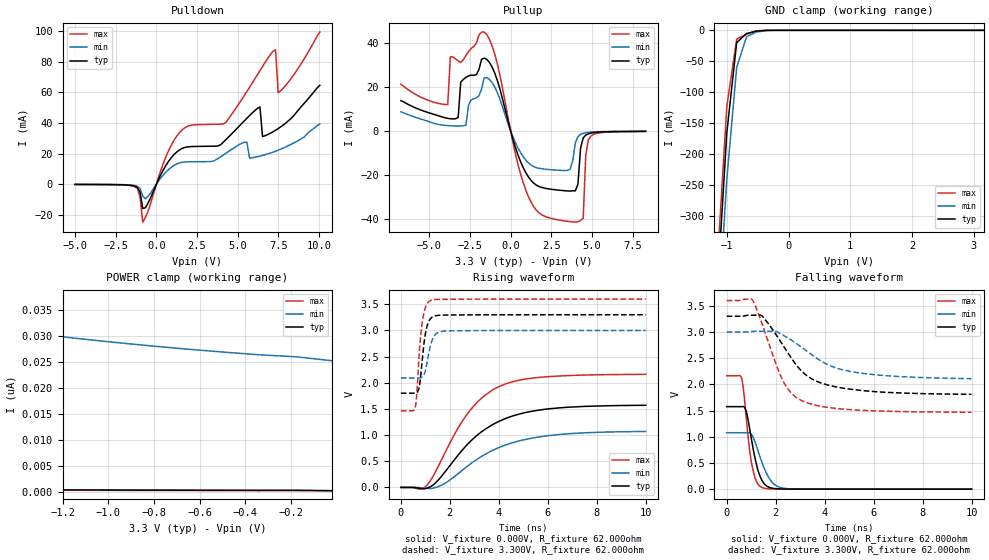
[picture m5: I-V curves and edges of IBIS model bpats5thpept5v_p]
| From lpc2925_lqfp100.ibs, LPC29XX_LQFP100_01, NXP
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| |   Rev 0.20 IBIS Model Design Automation Generation   |
| |   N O N - S I L I C O N   C O R R E L A T E D   |
| |   This IBIS [Model] is pre-Beta tactical support   |
| |  Note: this IBIS [Model] contains clamp curves generated   |
| |   through simulation which should not be relied upon   |
| Pccmos14 hliolib_nlm 4.0.1
|   0.18 um 3.3V pad library
|   six level metal
|   dual oxide
|   single threshold voltage
|   nominal line mixed supply
|   parasitic extracted netlists
| Process block c14
| bpats5thpept5v
|   Bidirectional Pad 3v3
|   3state Output
|   Plain Input
|   5ns Slew Rate control
|   CMOS
|   Programmable between
|   - (p1=0, p2=1) plain input
|   - (p1=0, p2=0) with Pull Up
|   - (p1=1, p2=1) with Pull Down
|   - (p1=1, p2=0) with Repeater
|   Characterized at Core 1.8V and I/O 3.3V
| Plain input Mode (p1=0, p2=1)
[Model]   bpats5thpept5v_p | of bpats5thpept5v
Model_type   I/O
Polarity   Non-Inverting
Enable   Active-Low
|  Reciever Thresholds
Vinl   = 0.99V
Vinh   = 2.31V
| AC Test Load Conditions
Vref   = 0
Cref   = 1.2e-11
Rref   = 1000000000
Vmeas   = 1.65
| [Process Range]   typical   min   max
| C_comp edge width   400.000ps   400.000ps   400.000ps
| C_comp Tstrobe   40.000fs   40.000fs   40.000fs
C_comp   2.539pF   2.402pF   2.679pF
[Temperature Range]   25   125   -40
[Voltage Range]   3.30V   3.00V   3.60V
[GND Clamp Reference]   0.00V   0.00V   0.00V
[Pulldown Reference]   0.00V   0.00V   0.00V
[POWER Clamp Reference]   3.30V   3.00V   3.60V
[Pullup Reference]   3.30V   3.00V   3.60V
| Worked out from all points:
|   slope of the pulldown table from 0 to 0.495 V, typ, clamps not added: 46.5 ohm
|   slope of the pullup table from 0 to 0.495 V, typ, clamps not added: 41.9 ohm
|   GND clamp passes 1 mA (typ) near -0.48 V on its own axis
|   rising waveform, V_fixture 0.000V, R_fixture 62.000ohm: 20-80 % time 2.15ns typ, 2.37ns min, 1.8ns max; typ from 0 V to 1.57 V
|   falling waveform, V_fixture 0.000V, R_fixture 62.000ohm: 20-80 % time 411ps typ, 539ps min, 319ps max; typ from 1.57 V to 0 V
|   rising waveform, V_fixture 3.300V, R_fixture 62.000ohm: 20-80 % time 225ps typ, 260ps min, 215ps max; typ from 1.8 V to 3.3 V
|   falling waveform, V_fixture 3.300V, R_fixture 62.000ohm: 20-80 % time 1.53ns typ, 1.95ns min, 1.1ns max; typ from 3.3 V to 1.81 V
[GND Clamp]
| ref voltage   0.00V   0.00V   0.00V
|   Voltage   I(typ)   I(min)   I(max)
-5V       -7.933A    -7.953A    -7.929A
-1.16V    -429.6mA   -501mA     -389.4mA
-1V       -166.1mA   -240.8mA   -123.1mA
-840mV    -19.82mA   -60.19mA   -14.18mA
-680mV    -5.225mA   -10.28mA   -6.152mA
-520mV    -1.304mA   -2.7mA     -818.1uA
-200mV    -132.3nA   -9.731uA   -2.769nA
3.16V     216.3pA    26.32nA    148.8pA
[Power Clamp]   | Vtable = Vcc - Vpad
| ref voltage   3.30V   3.00V   3.60V
|   Voltage   I(typ)   I(min)   I(max)
-6.74V    1.379nA    125.5nA    723.8pA
-4.66V    863pA      70.57nA    560.5pA
-2.42V    509.5pA    38.28nA    388.3pA
-2.26V    489.9pA    36.89nA    376pA
-2.1V     470.8pA    35.59nA    363.8pA
-1.78V    434.1pA    33.27nA    339.4pA
-1.62V    416.5pA    32.24nA    327.2pA
-1.3V     382.5pA    30.41nA    302.8pA
-820mV    334.3pA    28.18nA    266.3pA
-340mV    288.9pA    26.43nA    229.9pA
-180mV    281.7pA    26.06nA    265.9pA
-20mV     233pA      25.29nA    176.8pA
[Pulldown]
| ref voltage   0.00V   0.00V   0.00V
|   Voltage   I(typ)   I(min)   I(max)
-5V       -187.5uA   -145.8uA   -211.8uA
-1.32V    -1.32mA    -939.5uA   -1.723mA
-1V       -5.324mA   -2.961mA   -8.618mA
-840mV    -15.95mA   -7.735mA   -24.89mA
1.4V      22.26mA    13.79mA    33.48mA
4.28V     29.27mA    20.27mA    40.55mA
5.56V     43.15mA    27.33mA    60.63mA
6.36V     50.49mA    18.36mA    74.24mA
6.52V     31.16mA    18.79mA    76.97mA
7.32V     35.27mA    21.55mA    87.95mA
7.48V     36.36mA    22.22mA    59.78mA
10.04V    64.68mA    39.32mA    99.49mA
[Pullup]   | Vtable = Vcc - Vpad
| ref voltage   3.30V   3.00V   3.60V
|   Voltage   I(typ)   I(min)   I(max)
-6.74V    13.67mA    8.53mA     21.02mA
-3.86V    5.598mA    2.307mA    11.88mA
-3.7V     5.416mA    2.227mA    33.56mA
-2.74V    24.29mA    2.441mA    34.22mA
-1.62V    32.99mA    24.07mA    44.83mA
940mV     -19.18mA   -13.46mA   -27.14mA
2.86V     -27.01mA   -17.98mA   -40.52mA
3.98V     -27.37mA   -5.511mA   -41.66mA
4.46V     -3.36mA    -1.235mA   -39.89mA
4.62V     -2.02mA    -961.6uA   -11.27mA
4.94V     -1.105mA   -662.3uA   -2.417mA
8.3V      -310.5uA   -276.1uA   -365.1uA
[Ramp]
R_load   = 62.000ohm
|   dV/dt(typ)   dV/dt(min)   dV/dt(max)
dV/dt_r   720.631mV/2.205ns   482.682mV/2.365ns   1.049V/2.035ns
dV/dt_f   674.653mV/1.565ns   397.637mV/1.940ns   1.038V/1.245ns
[Rising Waveform]  | cubic spline decimation from 2001 points
V_fixture   = 0.000V
R_fixture   = 62.000ohm
|   Time   V(typ)   V(min)   V(max)
0s        2.482nV    412.2nV    1.344nV
765ps     -17.12mV   -3.168mV   -33.52mV
1.06ns    -16.23mV   -17.53mV   40.55mV
1.715ns   244.2mV    54.65mV    580.5mV
2.665ns   795.4mV    385.7mV    1.372V
3.255ns   1.049V     581mV      1.689V
3.95ns    1.25V      750.6mV    1.914V
4.895ns   1.409V     895.8mV    2.055V
6.08ns    1.504V     991.8mV    2.119V
10ns      1.57V      1.07V      2.162V
[Falling Waveform]  | cubic spline decimation from 2001 points
V_fixture   = 0.000V
R_fixture   = 62.000ohm
|   Time   V(typ)   V(min)   V(max)
0s        1.575V     1.077V     2.165V
610ps     1.576V     1.077V     2.118V
680ps     1.576V     1.076V     1.921V
790ps     1.496V     1.077V     1.406V
1.025ns   917.9mV    1.038V     476.3mV
1.205ns   493mV      837.1mV    157.9mV
1.445ns   165.7mV    505.2mV    32.07mV
1.885ns   16.15mV    117.4mV    4.029mV
2.4ns     2.893mV    14.38mV    1.574mV
10ns      49.83uV    118.5uV    23.14uV
[Rising Waveform]  | cubic spline decimation from 2001 points
V_fixture   = 3.300V
V_fixture_min = 3.000V
V_fixture_max = 3.600V
R_fixture   = 62.000ohm
|   Time   V(typ)   V(min)   V(max)
0s        1.801V     2.092V     1.464V
585ps     1.801V     2.093V     1.532V
640ps     1.809V     2.093V     1.718V
755ps     1.929V     2.092V     2.589V
885ps     2.487V     2.116V     3.188V
1.03ns    3.005V     2.289V     3.47V
1.21ns    3.225V     2.71V      3.572V
1.41ns    3.281V     2.923V     3.591V
1.82ns    3.294V     2.989V     3.596V
10ns      3.3V       3V         3.6V
[Falling Waveform]  | cubic spline decimation from 2001 points
V_fixture   = 3.300V
V_fixture_min = 3.000V
V_fixture_max = 3.600V
R_fixture   = 62.000ohm
|   Time   V(typ)   V(min)   V(max)
0s        3.3V       3V         3.6V
1.04ns    3.32V      3.009V     3.616V
1.45ns    3.304V     3.014V     3.151V
2.045ns   2.929V     3.004V     2.35V
2.325ns   2.727V     2.933V     2.045V
2.66ns    2.488V     2.839V     1.826V
3.1ns     2.235V     2.695V     1.683V
4.145ns   1.986V     2.371V     1.559V
5.13ns    1.904V     2.24V      1.515V
10ns      1.81V      2.109V     1.468V
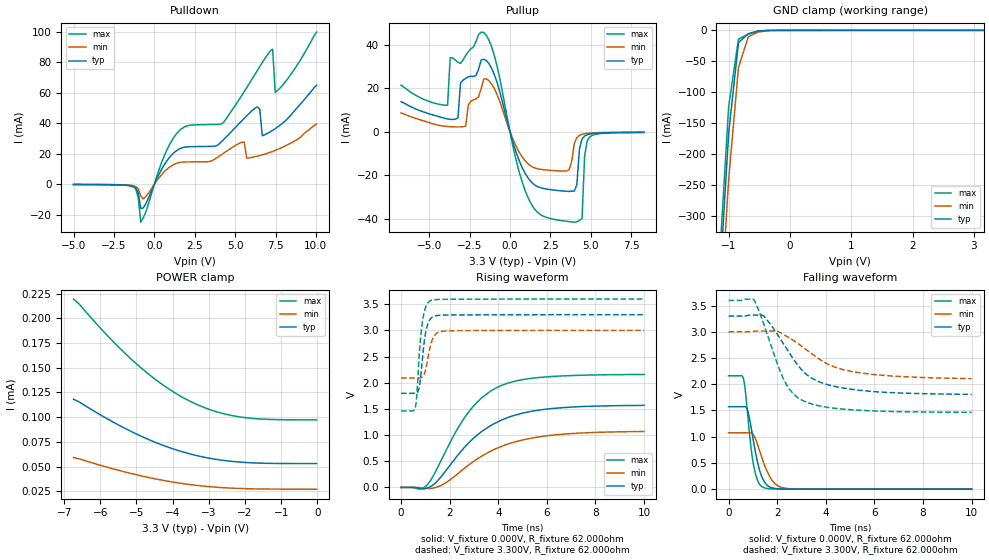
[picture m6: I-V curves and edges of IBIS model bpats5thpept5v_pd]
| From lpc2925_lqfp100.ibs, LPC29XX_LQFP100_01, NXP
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| |   Rev 0.20 IBIS Model Design Automation Generation   |
| |   N O N - S I L I C O N   C O R R E L A T E D   |
| |   This IBIS [Model] is pre-Beta tactical support   |
| |  Note: this IBIS [Model] contains clamp curves generated   |
| |   through simulation which should not be relied upon   |
| Pccmos14 hliolib_nlm 4.0.1
|   0.18 um 3.3V pad library
|   six level metal
|   dual oxide
|   single threshold voltage
|   nominal line mixed supply
|   parasitic extracted netlists
| Process block c14
| bpats5thpept5v
|   Bidirectional Pad 3v3
|   3state Output
|   Plain Input
|   5ns Slew Rate control
|   CMOS
|   Programmable between
|   - (p1=0, p2=1) plain input
|   - (p1=0, p2=0) with Pull Up
|   - (p1=1, p2=1) with Pull Down
|   - (p1=1, p2=0) with Repeater
|   Characterized at Core 1.8V and I/O 3.3V
| Pull Down Mode (p1=1, p2=1)
[Model]   bpats5thpept5v_pd | of bpats5thpept5v
Model_type   I/O
Polarity   Non-Inverting
Enable   Active-Low
|  Reciever Thresholds
Vinl   = 0.99V
Vinh   = 2.31V
| AC Test Load Conditions
Vref   = 0
Cref   = 1.2e-11
Rref   = 1000000000
Vmeas   = 1.65
| [Process Range]   typical   min   max
| C_comp edge width   400.000ps   400.000ps   400.000ps
| C_comp Tstrobe   40.000fs   40.000fs   40.000fs
C_comp   2.538pF   2.399pF   2.678pF
[Temperature Range]   25   125   -40
[Voltage Range]   3.30V   3.00V   3.60V
[GND Clamp Reference]   0.00V   0.00V   0.00V
[Pulldown Reference]   0.00V   0.00V   0.00V
[POWER Clamp Reference]   3.30V   3.00V   3.60V
[Pullup Reference]   3.30V   3.00V   3.60V
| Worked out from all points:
|   slope of the pulldown table from 0 to 0.495 V, typ, clamps not added: 46.5 ohm
|   slope of the pullup table from 0 to 0.495 V, typ, clamps not added: 41.9 ohm
|   GND clamp passes 1 mA (typ) near -0.48 V on its own axis
|   rising waveform, V_fixture 0.000V, R_fixture 62.000ohm: 20-80 % time 2.15ns typ, 2.37ns min, 1.8ns max; typ from 0 V to 1.57 V
|   falling waveform, V_fixture 0.000V, R_fixture 62.000ohm: 20-80 % time 410ps typ, 538ps min, 318ps max; typ from 1.57 V to 0 V
|   rising waveform, V_fixture 3.300V, R_fixture 62.000ohm: 20-80 % time 227ps typ, 261ps min, 216ps max; typ from 1.8 V to 3.3 V
|   falling waveform, V_fixture 3.300V, R_fixture 62.000ohm: 20-80 % time 1.53ns typ, 1.95ns min, 1.1ns max; typ from 3.3 V to 1.81 V
[GND Clamp]
| ref voltage   0.00V   0.00V   0.00V
|   Voltage   I(typ)   I(min)   I(max)
-5V       -7.933A    -7.953A    -7.929A
-1.16V    -429.6mA   -501mA     -389.4mA
-1V       -166.1mA   -240.8mA   -123.1mA
-840mV    -19.84mA   -60.2mA    -14.2mA
-680mV    -5.244mA   -10.3mA    -6.181mA
-520mV    -1.329mA   -2.711mA   -860.7uA
-200mV    -17.4uA    -20.02uA   -26.89uA
3.16V     53.01uA    27.08uA    97.28uA
[Power Clamp]   | Vtable = Vcc - Vpad
| ref voltage   3.30V   3.00V   3.60V
|   Voltage   I(typ)   I(min)   I(max)
-6.74V    118.1uA    59.14uA    219.6uA
-6.58V    115.3uA    57.74uA    214.3uA
-6.1V     104.5uA    52.36uA    194.3uA
-5.62V    94.49uA    47.37uA    175.6uA
-4.98V    82.54uA    41.46uA    153.3uA
-4.5V     74.82uA    37.65uA    138.8uA
-4.18V    70.31uA    35.43uA    130.3uA
-3.54V    62.97uA    31.84uA    116.5uA
-2.9V     57.87uA    29.37uA    106.8uA
-2.1V     54.38uA    27.71uA    100uA
-1.3V     53.2uA     27.16uA    97.67uA
-20mV     53.01uA    27.08uA    97.29uA
[Pulldown]
| ref voltage   0.00V   0.00V   0.00V
|   Voltage   I(typ)   I(min)   I(max)
-5V       -187.5uA   -145.8uA   -211.8uA
-1.32V    -1.32mA    -939.5uA   -1.723mA
-1V       -5.324mA   -2.961mA   -8.619mA
-840mV    -15.95mA   -7.735mA   -24.89mA
1.4V      22.26mA    13.79mA    33.48mA
4.28V     29.29mA    20.29mA    40.56mA
5.56V     43.21mA    27.5mA     60.72mA
6.36V     50.67mA    18.36mA    74.36mA
6.68V     31.78mA    19.27mA    79.81mA
7.32V     35.33mA    21.55mA    88.56mA
7.48V     36.44mA    22.22mA    60.22mA
10.04V    64.83mA    39.4mA     99.75mA
[Pullup]   | Vtable = Vcc - Vpad
| ref voltage   3.30V   3.00V   3.60V
|   Voltage   I(typ)   I(min)   I(max)
-6.74V    13.82mA    8.599mA    21.35mA
-3.86V    5.864mA    2.372mA    12.19mA
-3.7V     5.685mA    2.288mA    34.11mA
-2.74V    24.57mA    2.531mA    35.04mA
-1.62V    33.35mA    24.26mA    45.59mA
940mV     -19.18mA   -13.46mA   -27.15mA
2.86V     -27.01mA   -17.98mA   -40.52mA
3.98V     -27.37mA   -5.511mA   -41.66mA
4.46V     -3.361mA   -1.235mA   -39.89mA
4.62V     -2.02mA    -961.6uA   -11.27mA
4.94V     -1.105mA   -662.3uA   -2.418mA
8.3V      -310.5uA   -276.1uA   -365.1uA
[Ramp]
R_load   = 62.000ohm
|   dV/dt(typ)   dV/dt(min)   dV/dt(max)
dV/dt_r   719.302mV/2.205ns   482.029mV/2.365ns   1.047V/2.040ns
dV/dt_f   675.416mV/1.570ns   397.994mV/1.940ns   1.039V/1.245ns
[Rising Waveform]  | cubic spline decimation from 2001 points
V_fixture   = 0.000V
R_fixture   = 62.000ohm
|   Time   V(typ)   V(min)   V(max)
0s        2.445nV    410.1nV    1.304nV
765ps     -17.11mV   -3.168mV   -33.47mV
1.06ns    -16.17mV   -17.52mV   40.67mV
1.685ns   226.6mV    47.31mV    550.5mV
2.675ns   798.3mV    388.8mV    1.374V
3.335ns   1.074V     602.8mV    1.717V
4.07ns    1.273V     772.5mV    1.936V
4.98ns    1.416V     903.8mV    2.058V
6.15ns    1.504V     994mV      2.117V
10ns      1.567V     1.068V     2.158V
[Falling Waveform]  | cubic spline decimation from 2001 points
V_fixture   = 0.000V
R_fixture   = 62.000ohm
|   Time   V(typ)   V(min)   V(max)
0s        1.572V     1.075V     2.162V
610ps     1.573V     1.075V     2.114V
680ps     1.573V     1.075V     1.917V
790ps     1.493V     1.076V     1.401V
1.025ns   915mV      1.036V     471.2mV
1.195ns   510.1mV    849.5mV    165.8mV
1.415ns   190.6mV    541.8mV    37.07mV
1.875ns   16.42mV    121.2mV    3.959mV
2.38ns    2.935mV    15.21mV    1.58mV
10ns      49.48uV    118uV      22.85uV
[Rising Waveform]  | cubic spline decimation from 2001 points
V_fixture   = 3.300V
V_fixture_min = 3.000V
V_fixture_max = 3.600V
R_fixture   = 62.000ohm
|   Time   V(typ)   V(min)   V(max)
0s        1.798V     2.091V     1.461V
590ps     1.799V     2.091V     1.537V
640ps     1.806V     2.091V     1.714V
755ps     1.926V     2.091V     2.583V
875ps     2.436V     2.11V      3.148V
1.015ns   2.967V     2.256V     3.446V
1.21ns    3.222V     2.708V     3.568V
1.415ns   3.279V     2.923V     3.588V
1.79ns    3.292V     2.987V     3.593V
10ns      3.299V     2.999V     3.598V
[Falling Waveform]  | cubic spline decimation from 2001 points
V_fixture   = 3.300V
V_fixture_min = 3.000V
V_fixture_max = 3.600V
R_fixture   = 62.000ohm
|   Time   V(typ)   V(min)   V(max)
0s        3.299V     2.999V     3.598V
1.035ns   3.318V     3.008V     3.614V
1.45ns    3.301V     3.013V     3.145V
2.005ns   2.954V     3.008V     2.395V
2.305ns   2.738V     2.937V     2.059V
2.63ns    2.506V     2.846V     1.835V
3.07ns    2.245V     2.704V     1.685V
4.13ns    1.985V     2.373V     1.556V
5.155ns   1.899V     2.236V     1.51V
10ns      1.807V     2.107V     1.465V
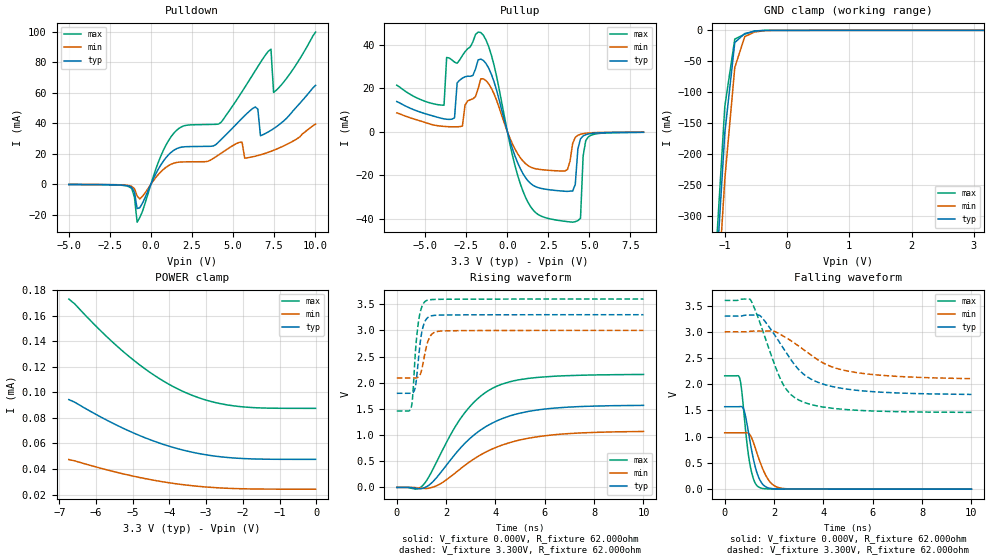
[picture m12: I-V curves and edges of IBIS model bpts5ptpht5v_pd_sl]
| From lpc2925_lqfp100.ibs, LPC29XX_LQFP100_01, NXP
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| |   Rev 0.20 IBIS Model Design Automation Generation   |
| |   N O N - S I L I C O N   C O R R E L A T E D   |
| |   This IBIS [Model] is pre-Beta tactical support   |
| |  Note: this IBIS [Model] contains clamp curves generated   |
| |   through simulation which should not be relied upon   |
| Pccmos14 hliolib_nlm 4.0.1
|   0.18 um 3.3V pad library
|   six level metal
|   dual oxide
|   single threshold voltage
|   nominal line mixed supply
|   parasitic extracted netlists
| Process block c14
| bpts5ptpht5v
|   Bidirectional Pad 3v3
|   3state Output
|   Plain Input
|   1ns Slew Rate control
|   CMOS
|   Programmable between
|   - (p1=0, p2=1) plain input
|   - (p1=0, p2=0) with Pull Up
|   - (p1=1, p2=1) with Pull Down
|   - (p1=1, p2=0) with Repeater
|   Characterized at Core 1.8V and I/O 3.3V
| Pull Down Mode (p1=1, p2=1)
[Model]   bpts5ptpht5v_pd_sl | of bpts5ptpht5v
Model_type   I/O
Polarity   Non-Inverting
Enable   Active-Low
|  Reciever Thresholds
Vinl   = 0.99V
Vinh   = 2.31V
| AC Test Load Conditions
Vref   = 0
Cref   = 1.2e-11
Rref   = 1000000000
Vmeas   = 1.65
| [Process Range]   typical   min   max
| C_comp edge width   400.000ps   400.000ps   400.000ps
| C_comp Tstrobe   40.000fs   40.000fs   40.000fs
C_comp   2.521pF   2.386pF   2.657pF
[Temperature Range]   25   125   -40
[Voltage Range]   3.30V   3.00V   3.60V
[GND Clamp Reference]   0.00V   0.00V   0.00V
[Pulldown Reference]   0.00V   0.00V   0.00V
[POWER Clamp Reference]   3.30V   3.00V   3.60V
[Pullup Reference]   3.30V   3.00V   3.60V
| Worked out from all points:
|   slope of the pulldown table from 0 to 0.495 V, typ, clamps not added: 46.5 ohm
|   slope of the pullup table from 0 to 0.495 V, typ, clamps not added: 41.9 ohm
|   GND clamp passes 1 mA (typ) near -0.48 V on its own axis
|   rising waveform, V_fixture 0.000V, R_fixture 62.000ohm: 20-80 % time 2.15ns typ, 2.37ns min, 1.8ns max; typ from 0 V to 1.57 V
|   falling waveform, V_fixture 0.000V, R_fixture 62.000ohm: 20-80 % time 408ps typ, 535ps min, 317ps max; typ from 1.57 V to 0 V
|   rising waveform, V_fixture 3.300V, R_fixture 62.000ohm: 20-80 % time 225ps typ, 261ps min, 216ps max; typ from 1.8 V to 3.3 V
|   falling waveform, V_fixture 3.300V, R_fixture 62.000ohm: 20-80 % time 1.54ns typ, 1.95ns min, 1.09ns max; typ from 3.3 V to 1.81 V
[GND Clamp]
| ref voltage   0.00V   0.00V   0.00V
|   Voltage   I(typ)   I(min)   I(max)
-5V       -7.933A    -7.953A    -7.929A
-1.16V    -429.6mA   -501mA     -389.4mA
-1V       -166mA     -240.8mA   -123.1mA
-840mV    -19.71mA   -60.08mA   -14.11mA
-680mV    -5.172mA   -10.16mA   -6.119mA
-520mV    -1.294mA   -2.638mA   -834.5uA
-200mV    -15.34uA   -18.05uA   -23.66uA
3.16V     47.55uA    24.23uA    87.44uA
[Power Clamp]   | Vtable = Vcc - Vpad
| ref voltage   3.30V   3.00V   3.60V
|   Voltage   I(typ)   I(min)   I(max)
-6.74V    94.28uA    47.4uA     172.9uA
-6.58V    92.21uA    46.36uA    169.1uA
-6.1V     84.26uA    42.38uA    154.6uA
-5.62V    76.9uA     38.71uA    141.1uA
-4.98V    68.19uA    34.37uA    125.2uA
-4.5V     62.6uA     31.59uA    114.9uA
-4.18V    59.37uA    29.99uA    109uA
-3.54V    54.16uA    27.42uA    99.49uA
-2.9V     50.63uA    25.7uA     93.05uA
-2.26V    48.64uA    24.74uA    89.4uA
-1.46V    47.7uA     24.3uA     87.7uA
-20mV     47.55uA    24.23uA    87.44uA
[Pulldown]
| ref voltage   0.00V   0.00V   0.00V
|   Voltage   I(typ)   I(min)   I(max)
-5V       -187.5uA   -145.7uA   -211.8uA
-1.32V    -1.32mA    -939.4uA   -1.723mA
-1V       -5.322mA   -2.96mA    -8.616mA
-840mV    -15.95mA   -7.733mA   -24.9mA
1.4V      22.26mA    13.79mA    33.48mA
4.28V     29.29mA    20.29mA    40.56mA
5.56V     43.21mA    27.48mA    60.71mA
6.36V     50.65mA    18.36mA    74.35mA
6.68V     31.77mA    19.27mA    79.79mA
7.32V     35.33mA    21.55mA    88.5mA
7.48V     36.43mA    22.22mA    60.17mA
10.04V    64.8mA     39.39mA    99.71mA
[Pullup]   | Vtable = Vcc - Vpad
| ref voltage   3.30V   3.00V   3.60V
|   Voltage   I(typ)   I(min)   I(max)
-6.74V    13.79mA    8.587mA    21.29mA
-3.86V    5.83mA     2.363mA    12.15mA
-3.7V     5.651mA    2.28mA     34.05mA
-2.74V    24.54mA    2.521mA    34.95mA
-1.62V    33.31mA    24.24mA    45.52mA
940mV     -19.18mA   -13.46mA   -27.15mA
2.86V     -27.01mA   -17.98mA   -40.52mA
3.98V     -27.38mA   -5.509mA   -41.66mA
4.46V     -3.36mA    -1.235mA   -39.9mA
4.62V     -2.02mA    -961.4uA   -11.27mA
4.94V     -1.105mA   -662.3uA   -2.417mA
8.3V      -310.5uA   -276uA     -365.2uA
[Ramp]
R_load   = 62.000ohm
|   dV/dt(typ)   dV/dt(min)   dV/dt(max)
dV/dt_r   719.455mV/2.205ns   482.125mV/2.365ns   1.047V/2.045ns
dV/dt_f   675.442mV/1.570ns   397.896mV/1.940ns   1.040V/1.240ns
[Rising Waveform]  | cubic spline decimation from 2001 points
V_fixture   = 0.000V
R_fixture   = 62.000ohm
|   Time   V(typ)   V(min)   V(max)
0s        2.032nV    363.7nV    1.043nV
765ps     -17.14mV   -3.167mV   -33.48mV
1.06ns    -16.04mV   -17.56mV   41.06mV
1.755ns   268.8mV    65.82mV    619.8mV
2.735ns   830.5mV    412.3mV    1.414V
3.405ns   1.099V     623.8mV    1.746V
4.065ns   1.273V     773.1mV    1.936V
4.945ns   1.413V     900.9mV    2.055V
6.2ns     1.507V     997.1mV    2.118V
10ns      1.567V     1.069V     2.158V
[Falling Waveform]  | cubic spline decimation from 2001 points
V_fixture   = 0.000V
R_fixture   = 62.000ohm
|   Time   V(typ)   V(min)   V(max)
0s        1.572V     1.075V     2.161V
610ps     1.573V     1.075V     2.113V
680ps     1.573V     1.075V     1.915V
790ps     1.493V     1.076V     1.399V
1.02ns    927.3mV    1.039V     479.7mV
1.205ns   488.5mV    834.5mV    147mV
1.415ns   186.4mV    540.2mV    30.8mV
1.83ns    17.25mV    141.1mV    3.446mV
2.33ns    2.559mV    15.88mV    1.454mV
10ns      41.34uV    103uV      18.25uV
[Rising Waveform]  | cubic spline decimation from 2001 points
V_fixture   = 3.300V
V_fixture_min = 3.000V
V_fixture_max = 3.600V
R_fixture   = 62.000ohm
|   Time   V(typ)   V(min)   V(max)
0s        1.798V     2.091V     1.461V
590ps     1.798V     2.091V     1.538V
640ps     1.805V     2.091V     1.715V
755ps     1.926V     2.091V     2.584V
880ps     2.459V     2.112V     3.164V
1.015ns   2.967V     2.256V     3.45V
1.2ns     3.216V     2.691V     3.568V
1.415ns   3.279V     2.924V     3.588V
1.755ns   3.291V     2.985V     3.593V
10ns      3.299V     2.999V     3.598V
[Falling Waveform]  | cubic spline decimation from 2001 points
V_fixture   = 3.300V
V_fixture_min = 3.000V
V_fixture_max = 3.600V
R_fixture   = 62.000ohm
|   Time   V(typ)   V(min)   V(max)
0s        3.299V     2.999V     3.598V
1.04ns    3.318V     3.009V     3.612V
1.45ns    3.301V     3.013V     3.145V
2.015ns   2.947V     3.007V     2.385V
2.34ns    2.713V     2.927V     2.023V
2.615ns   2.517V     2.851V     1.835V
3.06ns    2.251V     2.707V     1.687V
3.76ns    2.041V     2.471V     1.585V
4.93ns    1.909V     2.256V     1.517V
10ns      1.806V     2.107V     1.464V
